VERSION 5.7 ;
  NOWIREEXTENSIONATPIN ON ;
  DIVIDERCHAR "/" ;
  BUSBITCHARS "[]" ;
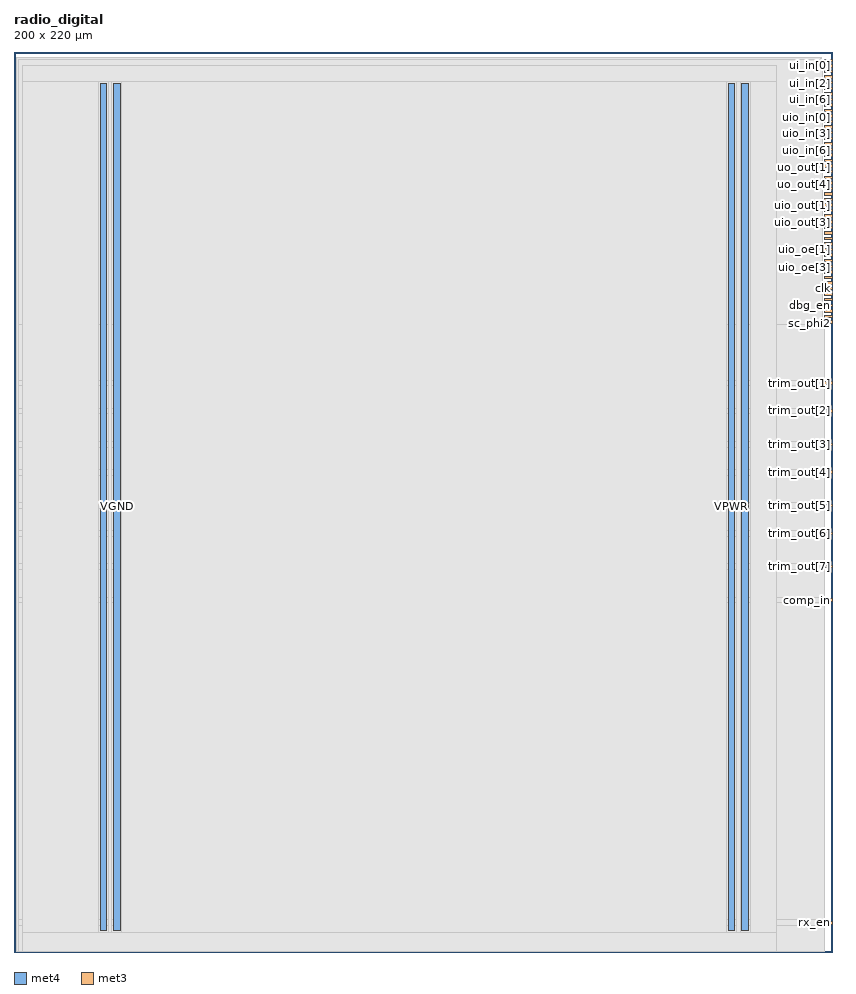
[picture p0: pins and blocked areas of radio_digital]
MACRO radio_digital
  CLASS BLOCK ;
  FOREIGN radio_digital ;
  ORIGIN 0.000 0.000 ;
  SIZE 200.000 BY 220.000 ;
  PIN VGND
    DIRECTION INOUT ;
    USE GROUND ;
    PORT
      LAYER met4 ;
        RECT 24.340 5.200 25.940 212.400 ;
    END
    PORT
      LAYER met4 ;
        RECT 177.940 5.200 179.540 212.400 ;
    END
  END VGND
  PIN VPWR
    DIRECTION INOUT ;
    USE POWER ;
    PORT
      LAYER met4 ;
        RECT 21.040 5.200 22.640 212.400 ;
    END
    PORT
      LAYER met4 ;
        RECT 174.640 5.200 176.240 212.400 ;
    END
  END VPWR
  PIN clk
    DIRECTION INPUT ;
    USE SIGNAL ;
    ANTENNAGATEAREA 1.704000 ;
    PORT
      LAYER met3 ;
        RECT 198.000 161.880 200.000 162.480 ;
    END
  END clk
  PIN comp_in
    DIRECTION INPUT ;
    USE SIGNAL ;
    ANTENNAGATEAREA 0.213000 ;
    PORT
      LAYER met3 ;
        RECT 198.000 85.720 200.000 86.320 ;
    END
  END comp_in
  PIN dbg_en
    DIRECTION OUTPUT ;
    USE SIGNAL ;
    ANTENNADIFFAREA 0.702900 ;
    PORT
      LAYER met3 ;
        RECT 198.000 157.800 200.000 158.400 ;
    END
  END dbg_en
  PIN rst_n
    DIRECTION INPUT ;
    USE SIGNAL ;
    ANTENNAGATEAREA 0.213000 ;
    PORT
      LAYER met3 ;
        RECT 198.000 217.640 200.000 218.240 ;
    END
  END rst_n
  PIN rx_en
    DIRECTION OUTPUT ;
    USE SIGNAL ;
    ANTENNADIFFAREA 0.702900 ;
    PORT
      LAYER met3 ;
        RECT 198.000 6.840 200.000 7.440 ;
    END
  END rx_en
  PIN sc_phi1
    DIRECTION OUTPUT ;
    USE SIGNAL ;
    ANTENNADIFFAREA 0.702900 ;
    PORT
      LAYER met3 ;
        RECT 198.000 156.440 200.000 157.040 ;
    END
  END sc_phi1
  PIN sc_phi2
    DIRECTION OUTPUT ;
    USE SIGNAL ;
    ANTENNADIFFAREA 0.702900 ;
    PORT
      LAYER met3 ;
        RECT 198.000 155.080 200.000 155.680 ;
    END
  END sc_phi2
  PIN trim_out[0]
    DIRECTION OUTPUT ;
    USE SIGNAL ;
    ANTENNADIFFAREA 0.702900 ;
    PORT
      LAYER met3 ;
        RECT 198.000 153.720 200.000 154.320 ;
    END
  END trim_out[0]
  PIN trim_out[1]
    DIRECTION OUTPUT ;
    USE SIGNAL ;
    ANTENNADIFFAREA 0.702900 ;
    PORT
      LAYER met3 ;
        RECT 198.000 138.760 200.000 139.360 ;
    END
  END trim_out[1]
  PIN trim_out[2]
    DIRECTION OUTPUT ;
    USE SIGNAL ;
    ANTENNADIFFAREA 0.702900 ;
    PORT
      LAYER met3 ;
        RECT 198.000 131.960 200.000 132.560 ;
    END
  END trim_out[2]
  PIN trim_out[3]
    DIRECTION OUTPUT ;
    USE SIGNAL ;
    ANTENNADIFFAREA 0.702900 ;
    PORT
      LAYER met3 ;
        RECT 198.000 123.800 200.000 124.400 ;
    END
  END trim_out[3]
  PIN trim_out[4]
    DIRECTION OUTPUT ;
    USE SIGNAL ;
    ANTENNADIFFAREA 0.702900 ;
    PORT
      LAYER met3 ;
        RECT 198.000 117.000 200.000 117.600 ;
    END
  END trim_out[4]
  PIN trim_out[5]
    DIRECTION OUTPUT ;
    USE SIGNAL ;
    ANTENNADIFFAREA 0.702900 ;
    PORT
      LAYER met3 ;
        RECT 198.000 108.840 200.000 109.440 ;
    END
  END trim_out[5]
  PIN trim_out[6]
    DIRECTION OUTPUT ;
    USE SIGNAL ;
    ANTENNADIFFAREA 0.702900 ;
    PORT
      LAYER met3 ;
        RECT 198.000 102.040 200.000 102.640 ;
    END
  END trim_out[6]
  PIN trim_out[7]
    DIRECTION OUTPUT ;
    USE SIGNAL ;
    ANTENNADIFFAREA 0.702900 ;
    PORT
      LAYER met3 ;
        RECT 198.000 93.880 200.000 94.480 ;
    END
  END trim_out[7]
  PIN tx_en
    DIRECTION OUTPUT ;
    USE SIGNAL ;
    ANTENNADIFFAREA 0.702900 ;
    PORT
      LAYER met3 ;
        RECT 198.000 160.520 200.000 161.120 ;
    END
  END tx_en
  PIN tx_en_n
    DIRECTION OUTPUT ;
    USE SIGNAL ;
    ANTENNADIFFAREA 0.702900 ;
    PORT
      LAYER met3 ;
        RECT 198.000 159.160 200.000 159.760 ;
    END
  END tx_en_n
  PIN ui_in[0]
    DIRECTION INPUT ;
    USE SIGNAL ;
    ANTENNAGATEAREA 0.213000 ;
    PORT
      LAYER met3 ;
        RECT 198.000 216.280 200.000 216.880 ;
    END
  END ui_in[0]
  PIN ui_in[1]
    DIRECTION INPUT ;
    USE SIGNAL ;
    ANTENNAGATEAREA 0.213000 ;
    PORT
      LAYER met3 ;
        RECT 198.000 214.920 200.000 215.520 ;
    END
  END ui_in[1]
  PIN ui_in[2]
    DIRECTION INPUT ;
    USE SIGNAL ;
    ANTENNAGATEAREA 0.213000 ;
    PORT
      LAYER met3 ;
        RECT 198.000 213.560 200.000 214.160 ;
    END
  END ui_in[2]
  PIN ui_in[3]
    DIRECTION INPUT ;
    USE SIGNAL ;
    ANTENNAGATEAREA 0.213000 ;
    PORT
      LAYER met3 ;
        RECT 198.000 212.200 200.000 212.800 ;
    END
  END ui_in[3]
  PIN ui_in[4]
    DIRECTION INPUT ;
    USE SIGNAL ;
    ANTENNAGATEAREA 0.213000 ;
    PORT
      LAYER met3 ;
        RECT 198.000 210.840 200.000 211.440 ;
    END
  END ui_in[4]
  PIN ui_in[5]
    DIRECTION INPUT ;
    USE SIGNAL ;
    ANTENNAGATEAREA 0.213000 ;
    PORT
      LAYER met3 ;
        RECT 198.000 209.480 200.000 210.080 ;
    END
  END ui_in[5]
  PIN ui_in[6]
    DIRECTION INPUT ;
    USE SIGNAL ;
    ANTENNAGATEAREA 0.213000 ;
    PORT
      LAYER met3 ;
        RECT 198.000 208.120 200.000 208.720 ;
    END
  END ui_in[6]
  PIN ui_in[7]
    DIRECTION INPUT ;
    USE SIGNAL ;
    ANTENNAGATEAREA 0.213000 ;
    PORT
      LAYER met3 ;
        RECT 198.000 206.760 200.000 207.360 ;
    END
  END ui_in[7]
  PIN uio_in[0]
    DIRECTION INPUT ;
    USE SIGNAL ;
    ANTENNAGATEAREA 0.213000 ;
    PORT
      LAYER met3 ;
        RECT 198.000 205.400 200.000 206.000 ;
    END
  END uio_in[0]
  PIN uio_in[1]
    DIRECTION INPUT ;
    USE SIGNAL ;
    ANTENNAGATEAREA 0.213000 ;
    PORT
      LAYER met3 ;
        RECT 198.000 204.040 200.000 204.640 ;
    END
  END uio_in[1]
  PIN uio_in[2]
    DIRECTION INPUT ;
    USE SIGNAL ;
    ANTENNAGATEAREA 0.213000 ;
    PORT
      LAYER met3 ;
        RECT 198.000 202.680 200.000 203.280 ;
    END
  END uio_in[2]
  PIN uio_in[3]
    DIRECTION INPUT ;
    USE SIGNAL ;
    ANTENNAGATEAREA 0.213000 ;
    PORT
      LAYER met3 ;
        RECT 198.000 201.320 200.000 201.920 ;
    END
  END uio_in[3]
  PIN uio_in[4]
    DIRECTION INPUT ;
    USE SIGNAL ;
    ANTENNAGATEAREA 0.213000 ;
    PORT
      LAYER met3 ;
        RECT 198.000 199.960 200.000 200.560 ;
    END
  END uio_in[4]
  PIN uio_in[5]
    DIRECTION INPUT ;
    USE SIGNAL ;
    ANTENNAGATEAREA 0.213000 ;
    PORT
      LAYER met3 ;
        RECT 198.000 198.600 200.000 199.200 ;
    END
  END uio_in[5]
  PIN uio_in[6]
    DIRECTION INPUT ;
    USE SIGNAL ;
    ANTENNAGATEAREA 0.213000 ;
    PORT
      LAYER met3 ;
        RECT 198.000 197.240 200.000 197.840 ;
    END
  END uio_in[6]
  PIN uio_in[7]
    DIRECTION INPUT ;
    USE SIGNAL ;
    ANTENNAGATEAREA 0.213000 ;
    PORT
      LAYER met3 ;
        RECT 198.000 195.880 200.000 196.480 ;
    END
  END uio_in[7]
  PIN uio_oe[0]
    DIRECTION OUTPUT ;
    USE SIGNAL ;
    PORT
      LAYER met3 ;
        RECT 198.000 172.760 200.000 173.360 ;
    END
  END uio_oe[0]
  PIN uio_oe[1]
    DIRECTION OUTPUT ;
    USE SIGNAL ;
    PORT
      LAYER met3 ;
        RECT 198.000 171.400 200.000 172.000 ;
    END
  END uio_oe[1]
  PIN uio_oe[2]
    DIRECTION OUTPUT ;
    USE SIGNAL ;
    PORT
      LAYER met3 ;
        RECT 198.000 170.040 200.000 170.640 ;
    END
  END uio_oe[2]
  PIN uio_oe[3]
    DIRECTION OUTPUT ;
    USE SIGNAL ;
    ANTENNADIFFAREA 0.702900 ;
    PORT
      LAYER met3 ;
        RECT 198.000 168.680 200.000 169.280 ;
    END
  END uio_oe[3]
  PIN uio_oe[4]
    DIRECTION OUTPUT ;
    USE SIGNAL ;
    ANTENNADIFFAREA 0.702900 ;
    PORT
      LAYER met3 ;
        RECT 198.000 167.320 200.000 167.920 ;
    END
  END uio_oe[4]
  PIN uio_oe[5]
    DIRECTION OUTPUT ;
    USE SIGNAL ;
    ANTENNADIFFAREA 0.702900 ;
    PORT
      LAYER met3 ;
        RECT 198.000 165.960 200.000 166.560 ;
    END
  END uio_oe[5]
  PIN uio_oe[6]
    DIRECTION OUTPUT ;
    USE SIGNAL ;
    ANTENNADIFFAREA 0.702900 ;
    PORT
      LAYER met3 ;
        RECT 198.000 164.600 200.000 165.200 ;
    END
  END uio_oe[6]
  PIN uio_oe[7]
    DIRECTION OUTPUT ;
    USE SIGNAL ;
    ANTENNADIFFAREA 0.702900 ;
    PORT
      LAYER met3 ;
        RECT 198.000 163.240 200.000 163.840 ;
    END
  END uio_oe[7]
  PIN uio_out[0]
    DIRECTION OUTPUT ;
    USE SIGNAL ;
    PORT
      LAYER met3 ;
        RECT 198.000 183.640 200.000 184.240 ;
    END
  END uio_out[0]
  PIN uio_out[1]
    DIRECTION OUTPUT ;
    USE SIGNAL ;
    PORT
      LAYER met3 ;
        RECT 198.000 182.280 200.000 182.880 ;
    END
  END uio_out[1]
  PIN uio_out[2]
    DIRECTION OUTPUT ;
    USE SIGNAL ;
    PORT
      LAYER met3 ;
        RECT 198.000 180.920 200.000 181.520 ;
    END
  END uio_out[2]
  PIN uio_out[3]
    DIRECTION OUTPUT ;
    USE SIGNAL ;
    ANTENNADIFFAREA 0.702900 ;
    PORT
      LAYER met3 ;
        RECT 198.000 179.560 200.000 180.160 ;
    END
  END uio_out[3]
  PIN uio_out[4]
    DIRECTION OUTPUT ;
    USE SIGNAL ;
    ANTENNADIFFAREA 0.702900 ;
    PORT
      LAYER met3 ;
        RECT 198.000 178.200 200.000 178.800 ;
    END
  END uio_out[4]
  PIN uio_out[5]
    DIRECTION OUTPUT ;
    USE SIGNAL ;
    ANTENNADIFFAREA 0.702900 ;
    PORT
      LAYER met3 ;
        RECT 198.000 176.840 200.000 177.440 ;
    END
  END uio_out[5]
  PIN uio_out[6]
    DIRECTION OUTPUT ;
    USE SIGNAL ;
    ANTENNADIFFAREA 0.702900 ;
    PORT
      LAYER met3 ;
        RECT 198.000 175.480 200.000 176.080 ;
    END
  END uio_out[6]
  PIN uio_out[7]
    DIRECTION OUTPUT ;
    USE SIGNAL ;
    ANTENNADIFFAREA 0.702900 ;
    PORT
      LAYER met3 ;
        RECT 198.000 174.120 200.000 174.720 ;
    END
  END uio_out[7]
  PIN uo_out[0]
    DIRECTION OUTPUT ;
    USE SIGNAL ;
    ANTENNADIFFAREA 0.702900 ;
    PORT
      LAYER met3 ;
        RECT 198.000 194.520 200.000 195.120 ;
    END
  END uo_out[0]
  PIN uo_out[1]
    DIRECTION OUTPUT ;
    USE SIGNAL ;
    ANTENNADIFFAREA 0.702900 ;
    PORT
      LAYER met3 ;
        RECT 198.000 193.160 200.000 193.760 ;
    END
  END uo_out[1]
  PIN uo_out[2]
    DIRECTION OUTPUT ;
    USE SIGNAL ;
    ANTENNADIFFAREA 0.702900 ;
    PORT
      LAYER met3 ;
        RECT 198.000 191.800 200.000 192.400 ;
    END
  END uo_out[2]
  PIN uo_out[3]
    DIRECTION OUTPUT ;
    USE SIGNAL ;
    ANTENNADIFFAREA 0.702900 ;
    PORT
      LAYER met3 ;
        RECT 198.000 190.440 200.000 191.040 ;
    END
  END uo_out[3]
  PIN uo_out[4]
    DIRECTION OUTPUT ;
    USE SIGNAL ;
    ANTENNADIFFAREA 0.702900 ;
    PORT
      LAYER met3 ;
        RECT 198.000 189.080 200.000 189.680 ;
    END
  END uo_out[4]
  PIN uo_out[5]
    DIRECTION OUTPUT ;
    USE SIGNAL ;
    ANTENNADIFFAREA 0.702900 ;
    PORT
      LAYER met3 ;
        RECT 198.000 187.720 200.000 188.320 ;
    END
  END uo_out[5]
  PIN uo_out[6]
    DIRECTION OUTPUT ;
    USE SIGNAL ;
    ANTENNADIFFAREA 0.702900 ;
    PORT
      LAYER met3 ;
        RECT 198.000 186.360 200.000 186.960 ;
    END
  END uo_out[6]
  PIN uo_out[7]
    DIRECTION OUTPUT ;
    USE SIGNAL ;
    ANTENNADIFFAREA 0.702900 ;
    PORT
      LAYER met3 ;
        RECT 198.000 185.000 200.000 185.600 ;
    END
  END uo_out[7]
  OBS
      LAYER nwell ;
        RECT 5.330 5.355 194.310 212.245 ;
      LAYER li1 ;
        RECT 5.520 5.355 194.120 212.245 ;
      LAYER met1 ;
        RECT 0.530 0.040 197.270 218.580 ;
      LAYER met2 ;
        RECT 0.560 0.010 197.250 218.610 ;
      LAYER met3 ;
        RECT 0.985 153.320 197.600 218.105 ;
        RECT 0.985 139.760 198.000 153.320 ;
        RECT 0.985 138.360 197.600 139.760 ;
        RECT 0.985 132.960 198.000 138.360 ;
        RECT 0.985 131.560 197.600 132.960 ;
        RECT 0.985 124.800 198.000 131.560 ;
        RECT 0.985 123.400 197.600 124.800 ;
        RECT 0.985 118.000 198.000 123.400 ;
        RECT 0.985 116.600 197.600 118.000 ;
        RECT 0.985 109.840 198.000 116.600 ;
        RECT 0.985 108.440 197.600 109.840 ;
        RECT 0.985 103.040 198.000 108.440 ;
        RECT 0.985 101.640 197.600 103.040 ;
        RECT 0.985 94.880 198.000 101.640 ;
        RECT 0.985 93.480 197.600 94.880 ;
        RECT 0.985 86.720 198.000 93.480 ;
        RECT 0.985 85.320 197.600 86.720 ;
        RECT 0.985 7.840 198.000 85.320 ;
        RECT 0.985 6.440 197.600 7.840 ;
        RECT 0.985 0.180 198.000 6.440 ;
      LAYER met4 ;
        RECT 2.135 212.800 186.465 216.745 ;
        RECT 2.135 4.800 20.640 212.800 ;
        RECT 23.040 4.800 23.940 212.800 ;
        RECT 26.340 4.800 174.240 212.800 ;
        RECT 176.640 4.800 177.540 212.800 ;
        RECT 179.940 4.800 186.465 212.800 ;
        RECT 2.135 0.175 186.465 4.800 ;
  END
END radio_digital
END LIBRARY

